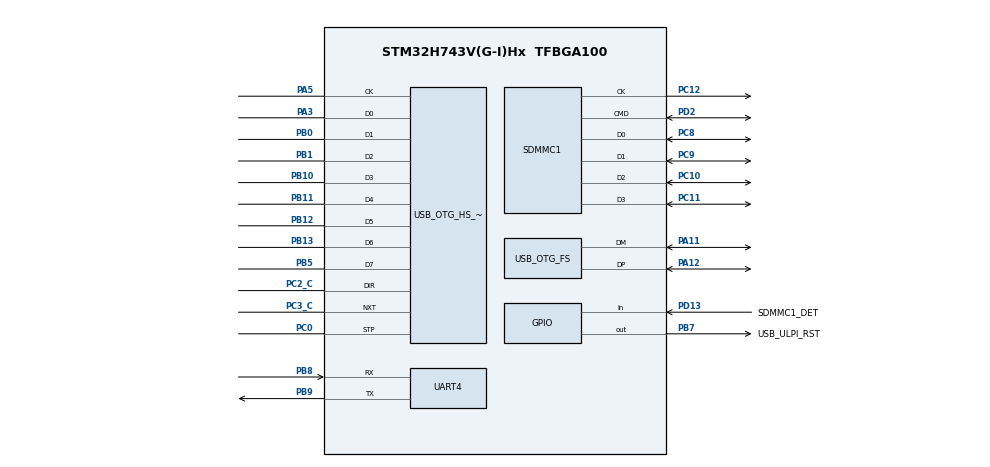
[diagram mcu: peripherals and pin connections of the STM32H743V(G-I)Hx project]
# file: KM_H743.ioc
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CORTEX_M7.default_mode_Activation=1
FATFS.BSP.number=1
FATFS._CODE_PAGE=949
FATFS._FS_EXFAT=1
FATFS._FS_RPATH=2
FATFS._USE_CHMOD=1
FATFS._USE_EXPAND=1
FATFS._USE_FIND=1
FATFS._USE_LFN=2
FATFS._USE_TRIM=0
FATFS0.BSP.STBoard=false
FATFS0.BSP.api=Unknown
FATFS0.BSP.instance=PD13
FATFS0.BSP.ip=GPIO
FATFS0.BSP.mode=Input
FATFS0.BSP.name=Detect_SDIO
FATFS0.BSP.solution=PD13
FREERTOS.Tasks01=defaultTask,24,1024,StartDefaultTask,Default,NULL,Static,defaultTaskStack,defaultTaskControl
FREERTOS.configMINIMAL_STACK_SIZE=512
FREERTOS.configTOTAL_HEAP_SIZE=8192
FREERTOS.configUSE_NEWLIB_REENTRANT=0
Mcu.Family=STM32H7
Mcu.Name=STM32H743V(G-I)Hx
Mcu.Package=TFBGA100
NVIC.OTG_FS_EP1_IN_IRQn=true\:5\:0\:false\:false\:true\:true\:true\:true\:true
NVIC.OTG_FS_EP1_OUT_IRQn=true\:5\:0\:false\:false\:true\:true\:true\:true\:true
NVIC.OTG_FS_IRQn=true\:5\:0\:false\:false\:true\:true\:true\:true\:true
NVIC.PriorityGroup=NVIC_PRIORITYGROUP_4
NVIC.TIM1_UP_IRQn=true\:15\:0\:false\:false\:true\:false\:false\:true\:true
NVIC.TimeBase=TIM1_UP_IRQn
NVIC.TimeBaseIP=TIM1
PA11.Mode=Device_Only
PA11.Signal=USB_OTG_FS_DM
PA12.Mode=Device_Only
PA12.Signal=USB_OTG_FS_DP
PA13\ (JTMS/SWDIO).Mode=Serial_Wire
PA13\ (JTMS/SWDIO).Signal=DEBUG_JTMS-SWDIO
PA14\ (JTCK/SWCLK).Mode=Serial_Wire
PA14\ (JTCK/SWCLK).Signal=DEBUG_JTCK-SWCLK
PA3.Mode=Device_HS
PA3.Signal=USB_OTG_HS_ULPI_D0
PA5.Mode=Device_HS
PA5.Signal=USB_OTG_HS_ULPI_CK
PB0.Mode=Device_HS
PB0.Signal=USB_OTG_HS_ULPI_D1
PB1.Mode=Device_HS
PB1.Signal=USB_OTG_HS_ULPI_D2
PB10.Mode=Device_HS
PB10.Signal=USB_OTG_HS_ULPI_D3
PB11.Mode=Device_HS
PB11.Signal=USB_OTG_HS_ULPI_D4
PB12.Mode=Device_HS
PB12.Signal=USB_OTG_HS_ULPI_D5
PB13.Mode=Device_HS
PB13.Signal=USB_OTG_HS_ULPI_D6
PB5.Mode=Device_HS
PB5.Signal=USB_OTG_HS_ULPI_D7
PB7.GPIO_Label=USB_ULPI_RST
PB7.Signal=GPIO_Output
PB8.Mode=Asynchronous
PB8.Signal=UART4_RX
PB9.Mode=Asynchronous
PB9.Signal=UART4_TX
PC0.Mode=Device_HS
PC0.Signal=USB_OTG_HS_ULPI_STP
PC10.Mode=SD_4_bits_Wide_bus
PC10.Signal=SDMMC1_D2
PC11.Mode=SD_4_bits_Wide_bus
PC11.Signal=SDMMC1_D3
PC12.Mode=SD_4_bits_Wide_bus
PC12.Signal=SDMMC1_CK
PC14-OSC32_IN\ (OSC32_IN).Mode=LSE-External-Oscillator
PC14-OSC32_IN\ (OSC32_IN).PinAttribute=Free
PC14-OSC32_IN\ (OSC32_IN).Signal=RCC_OSC32_IN
PC15-OSC32_OUT\ (OSC32_OUT).Mode=LSE-External-Oscillator
PC15-OSC32_OUT\ (OSC32_OUT).Signal=RCC_OSC32_OUT
PC2_C.Mode=Device_HS
PC2_C.Signal=USB_OTG_HS_ULPI_DIR
PC3_C.Mode=Device_HS
PC3_C.Signal=USB_OTG_HS_ULPI_NXT
PC8.Mode=SD_4_bits_Wide_bus
PC8.Signal=SDMMC1_D0
PC9.Mode=SD_4_bits_Wide_bus
PC9.Signal=SDMMC1_D1
PD13.GPIO_Label=SDMMC1_DET
PD13.Signal=GPIO_Input
PD2.Mode=SD_4_bits_Wide_bus
PD2.Signal=SDMMC1_CMD
PH0-OSC_IN\ (PH0).Mode=HSE-External-Oscillator
PH0-OSC_IN\ (PH0).Signal=RCC_OSC_IN
PH1-OSC_OUT\ (PH1).Mode=HSE-External-Oscillator
PH1-OSC_OUT\ (PH1).Signal=RCC_OSC_OUT
ProjectManager.HeapSize=0x200
ProjectManager.StackSize=0x400
ProjectManager.TargetToolchain=STM32CubeIDE
RCC.ADCFreq_Value=25000000
RCC.APB1Freq_Value=120000000
RCC.APB2Freq_Value=120000000
RCC.APB3Freq_Value=120000000
RCC.APB4Freq_Value=120000000
RCC.CortexFreq_Value=480000000
RCC.D1PPRE=RCC_APB3_DIV2
RCC.D2PPRE1=RCC_APB1_DIV2
RCC.D2PPRE2=RCC_APB2_DIV2
RCC.D3PPRE=RCC_APB4_DIV2
RCC.DIVM1=5
RCC.DIVM2=5
RCC.DIVM3=5
RCC.DIVN1=192
RCC.DIVN2=10
RCC.DIVN3=120
RCC.DIVP3=3
RCC.DIVQ1=20
RCC.DIVQ3=5
RCC.HCLKFreq_Value=240000000
RCC.HPRE=RCC_HCLK_DIV2
RCC.HSE_VALUE=25000000
RCC.PLL1_VCI_Range-AdvancedSettings=RCC_PLL1VCIRANGE_0
RCC.PLL2_VCI_Range-AdvancedSettings=RCC_PLL2VCIRANGE_0
RCC.PLL2_VCO_SEL-AdvancedSettings=RCC_PLL2VCOWIDE
RCC.PLL3_VCI_Range-AdvancedSettings=RCC_PLL3VCIRANGE_0
RCC.PLLSourceVirtual=RCC_PLLSOURCE_HSE
RCC.SPI123CLockSelection=RCC_SPI123CLKSOURCE_PLL3
RCC.SYSCLKFreq_VALUE=480000000
RCC.SYSCLKSource=RCC_SYSCLKSOURCE_PLLCLK
RCC.Spi45ClockSelection=RCC_SPI45CLKSOURCE_PLL3
RCC.USBFreq_Value=48000000
USB_OTG_FS.VirtualMode=Device_Only
SDMMC1.ClockDiv=1
USB_OTG_HS.VirtualMode-Device_HS=Device_HS
VP_FATFS_VS_SDIO.Mode=SDIO
VP_FREERTOS_VS_CMSIS_V2.Mode=CMSIS_V2
VP_MEMORYMAP_VS_MEMORYMAP.Mode=CurAppReg
VP_SYS_VS_tim1.Mode=TIM1
board=custom

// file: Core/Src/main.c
/* USER CODE BEGIN Header */
/**
  ******************************************************************************
  * @file           : main.c
  * @brief          : Main program body
  ******************************************************************************
  * @attention
  *
  * Copyright (c) 2026 STMicroelectronics.
  * All rights reserved.
  *
  * This software is licensed under terms that can be found in the LICENSE file
  * in the root directory of this software component.
  * If no LICENSE file comes with this software, it is provided AS-IS.
  *
  ******************************************************************************
  */
/* USER CODE END Header */
#include "main.h"
#include "cmsis_os.h"
#include "fatfs.h"

/* USER CODE BEGIN Includes */
#include "management_fs.h"
#include "target_usb.h"
#include "FreeRTOS.h"
#include "task.h"
#include <stdbool.h>

/* USER CODE END Includes */

SD_HandleTypeDef hsd1;

UART_HandleTypeDef huart4;

/* Definitions for defaultTask */
/* Static FreeRTOS storage for the initial system/diagnostics task. */
static StaticTask_t defaultTaskControl;
static StackType_t defaultTaskStack[4096 / sizeof(StackType_t)]
    __attribute__((section(".rtos_stacks"), aligned(8)));
osThreadId_t defaultTaskHandle;
const osThreadAttr_t defaultTask_attributes = {
  .name = "defaultTask",
  .cb_mem = &defaultTaskControl,
  .cb_size = sizeof(defaultTaskControl),
  .stack_mem = defaultTaskStack,
  .stack_size = sizeof(defaultTaskStack),
  .priority = (osPriority_t) osPriorityNormal,
};

void SystemClock_Config(void);
static void MX_GPIO_Init(void);
static void MX_SDMMC1_SD_Init(void);
static void MX_UART4_Init(void);
void StartDefaultTask(void *argument);

int main(void)
{

  /* MCU Configuration--------------------------------------------------------*/

  /* Reset of all peripherals, Initializes the Flash interface and the Systick. */
  if (HAL_Init() != HAL_OK)
  {
    Error_Handler();
  }

  /* Configure the system clock */
  SystemClock_Config();

  /* Initialize all configured peripherals */
  MX_GPIO_Init();
  MX_SDMMC1_SD_Init();
  MX_UART4_Init();
  MX_FATFS_Init();

  /* Init scheduler */
  if (osKernelInitialize() != osOK)
  {
    Error_Handler();
  }

  /* Create the thread(s) */
  /* creation of defaultTask */
  defaultTaskHandle = osThreadNew(StartDefaultTask, NULL, &defaultTask_attributes);

  /* USER CODE BEGIN RTOS_THREADS */
  if (defaultTaskHandle == NULL || retSD != 0U)
  {
    Error_Handler();
  }
  UsbBoard_InitClock();
#ifndef MINIKMB_USB_HS_ONLY
  ManagementUsb_Start();
#endif
  TargetUsb_Start();
  /* USER CODE END RTOS_THREADS */

  /* Start scheduler */
  (void)osKernelStart();
  Error_Handler();

  /* We should never get here as control is now taken by the scheduler */

  /* Infinite loop */
  while (1)
  {

  }
}

void SystemClock_Config(void)
{
  RCC_OscInitTypeDef RCC_OscInitStruct = {0};
  RCC_ClkInitTypeDef RCC_ClkInitStruct = {0};

  /** Supply configuration update enable
  */
  if (HAL_PWREx_ConfigSupply(PWR_LDO_SUPPLY) != HAL_OK)
  {
    Error_Handler();
  }

  /** Configure the main internal regulator output voltage
  */
  /* Keep USB/RNG at 48 MHz while reducing Cortex-M7 and AHB power. */
  bool fast_clock = false;
#if defined(MINIKMB_CPU_480MHZ) && MINIKMB_CPU_480MHZ
  fast_clock = HAL_GetREVID() == REV_ID_V;
#endif
  const uint32_t vos = fast_clock ? PWR_REGULATOR_VOLTAGE_SCALE0 : PWR_REGULATOR_VOLTAGE_SCALE1;
  if (HAL_PWREx_ControlVoltageScaling(vos) != HAL_OK)
  {
    Error_Handler();
  }

  /** Initializes the RCC Oscillators according to the specified parameters
  * in the RCC_OscInitTypeDef structure.
  */
  RCC_OscInitStruct.OscillatorType = RCC_OSCILLATORTYPE_HSE;
  RCC_OscInitStruct.HSEState = RCC_HSE_ON;
  RCC_OscInitStruct.PLL.PLLState = RCC_PLL_ON;
  RCC_OscInitStruct.PLL.PLLSource = RCC_PLLSOURCE_HSE;
  RCC_OscInitStruct.PLL.PLLM = 5;
  if (!fast_clock)
  {
    /* 25 / 5 * 96 = 480 MHz VCO; 240 MHz CPU, 120 MHz AHB, Q=10. */
    RCC_OscInitStruct.PLL.PLLN = 96;
    RCC_OscInitStruct.PLL.PLLQ = 10;
  }
  else
  {
    RCC_OscInitStruct.PLL.PLLN = 192;
    RCC_OscInitStruct.PLL.PLLQ = 20;
  }
  RCC_OscInitStruct.PLL.PLLP = 2;
  RCC_OscInitStruct.PLL.PLLR = 2;
  RCC_OscInitStruct.PLL.PLLRGE = RCC_PLL1VCIRANGE_2;
  RCC_OscInitStruct.PLL.PLLVCOSEL = RCC_PLL1VCOWIDE;
  RCC_OscInitStruct.PLL.PLLFRACN = 0;
  if (HAL_RCC_OscConfig(&RCC_OscInitStruct) != HAL_OK)
  {
    Error_Handler();
  }

  /** Initializes the CPU, AHB and APB buses clocks
  */
  RCC_ClkInitStruct.ClockType = RCC_CLOCKTYPE_HCLK|RCC_CLOCKTYPE_SYSCLK
                              |RCC_CLOCKTYPE_PCLK1|RCC_CLOCKTYPE_PCLK2
                              |RCC_CLOCKTYPE_D3PCLK1|RCC_CLOCKTYPE_D1PCLK1;
  RCC_ClkInitStruct.SYSCLKSource = RCC_SYSCLKSOURCE_PLLCLK;
  RCC_ClkInitStruct.SYSCLKDivider = RCC_SYSCLK_DIV1;
  RCC_ClkInitStruct.AHBCLKDivider = RCC_HCLK_DIV2;
  RCC_ClkInitStruct.APB3CLKDivider = RCC_APB3_DIV2;
  RCC_ClkInitStruct.APB1CLKDivider = RCC_APB1_DIV2;
  RCC_ClkInitStruct.APB2CLKDivider = RCC_APB2_DIV2;
  RCC_ClkInitStruct.APB4CLKDivider = RCC_APB4_DIV2;

  if (HAL_RCC_ClockConfig(&RCC_ClkInitStruct, FLASH_LATENCY_4) != HAL_OK)
  {
    Error_Handler();
  }
}

static void MX_SDMMC1_SD_Init(void)
{

  hsd1.Instance = SDMMC1;
  hsd1.Init.ClockEdge = SDMMC_CLOCK_EDGE_RISING;
  hsd1.Init.ClockPowerSave = SDMMC_CLOCK_POWER_SAVE_DISABLE;
  hsd1.Init.BusWide = SDMMC_BUS_WIDE_4B;
  hsd1.Init.HardwareFlowControl = SDMMC_HARDWARE_FLOW_CONTROL_DISABLE;
  /* Card I/O starts from FatFs disk_initialize in task context. */
  hsd1.Init.ClockDiv = 1;

}

static void MX_UART4_Init(void)
{

  huart4.Instance = UART4;
  huart4.Init.BaudRate = 115200;
  huart4.Init.WordLength = UART_WORDLENGTH_8B;
  huart4.Init.StopBits = UART_STOPBITS_1;
  huart4.Init.Parity = UART_PARITY_NONE;
  huart4.Init.Mode = UART_MODE_TX_RX;
  huart4.Init.HwFlowCtl = UART_HWCONTROL_NONE;
  huart4.Init.OverSampling = UART_OVERSAMPLING_16;
  huart4.Init.OneBitSampling = UART_ONE_BIT_SAMPLE_DISABLE;
  huart4.Init.ClockPrescaler = UART_PRESCALER_DIV1;
  huart4.AdvancedInit.AdvFeatureInit = UART_ADVFEATURE_NO_INIT;
  if (HAL_UART_Init(&huart4) != HAL_OK)
  {
    Error_Handler();
  }
  if (HAL_UARTEx_SetTxFifoThreshold(&huart4, UART_TXFIFO_THRESHOLD_1_8) != HAL_OK)
  {
    Error_Handler();
  }
  if (HAL_UARTEx_SetRxFifoThreshold(&huart4, UART_RXFIFO_THRESHOLD_1_8) != HAL_OK)
  {
    Error_Handler();
  }
  if (HAL_UARTEx_DisableFifoMode(&huart4) != HAL_OK)
  {
    Error_Handler();
  }

}

static void MX_GPIO_Init(void)
{
  GPIO_InitTypeDef GPIO_InitStruct = {0};

  /* GPIO Ports Clock Enable */
  __HAL_RCC_GPIOC_CLK_ENABLE();
  __HAL_RCC_GPIOB_CLK_ENABLE();
  __HAL_RCC_GPIOA_CLK_ENABLE();
  __HAL_RCC_GPIOD_CLK_ENABLE();
  __HAL_RCC_GPIOH_CLK_ENABLE();

  /*Configure GPIO pin Output Level */
  HAL_GPIO_WritePin(USB_ULPI_RST_GPIO_Port, USB_ULPI_RST_Pin, GPIO_PIN_RESET);

  /*Configure GPIO pin : USB_ULPI_RST_Pin */
  GPIO_InitStruct.Pin = USB_ULPI_RST_Pin;
  GPIO_InitStruct.Mode = GPIO_MODE_OUTPUT_PP;
  GPIO_InitStruct.Pull = GPIO_NOPULL;
  GPIO_InitStruct.Speed = GPIO_SPEED_FREQ_LOW;
  HAL_GPIO_Init(USB_ULPI_RST_GPIO_Port, &GPIO_InitStruct);

  /*Configure GPIO pin : SDMMC1_DET_Pin */
  GPIO_InitStruct.Pin = SDMMC1_DET_Pin;
  GPIO_InitStruct.Mode = GPIO_MODE_INPUT;
  GPIO_InitStruct.Pull = GPIO_NOPULL;
  HAL_GPIO_Init(SDMMC1_DET_GPIO_Port, &GPIO_InitStruct);

}

void StartDefaultTask(void *argument)
{
  /* USER CODE BEGIN 5 */
  /* Infinite loop */
  for(;;)
  {
    osDelay(1000);
  }
  /* USER CODE END 5 */
}

void HAL_TIM_PeriodElapsedCallback(TIM_HandleTypeDef *htim)
{
  if (htim->Instance == TIM1)
  {
    HAL_IncTick();
  }
}

void Error_Handler(void)
{
  __disable_irq();
  while (1)
  {
  }
}

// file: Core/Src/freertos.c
/* USER CODE BEGIN Header */
/**
  ******************************************************************************
  * File Name          : freertos.c
  * Description        : Code for freertos applications
  ******************************************************************************
  * @attention
  *
  * Copyright (c) 2026 STMicroelectronics.
  * All rights reserved.
  *
  * This software is licensed under terms that can be found in the LICENSE file
  * in the root directory of this software component.
  * If no LICENSE file comes with this software, it is provided AS-IS.
  *
  ******************************************************************************
  */
/* USER CODE END Header */

#include "FreeRTOS.h"
#include "task.h"
#include "main.h"

/* USER CODE BEGIN Includes */
#include <stdint.h>

/* USER CODE END Includes */

/* USER CODE BEGIN Variables */
uint8_t ucHeap[configTOTAL_HEAP_SIZE] __attribute__((section(".rtos_heap"), aligned(32)));

static StaticTask_t idleControl;
static StaticTask_t timerControl;
static StackType_t idleStack[configMINIMAL_STACK_SIZE]
    __attribute__((section(".rtos_stacks"), aligned(8)));
static StackType_t timerStack[configTIMER_TASK_STACK_DEPTH]
    __attribute__((section(".rtos_stacks"), aligned(8)));

/* Available to SWD before the USB diagnostic transport is implemented. */
static volatile uint32_t allocationFailures;

/* USER CODE END Variables */

/* USER CODE BEGIN Application */
extern uint32_t g_pfnVectors[];
extern uint64_t __axi_start__[], __axi_end__[];
extern uint32_t __d2_start__[], __d2_end__[];

void BoardMemory_Init(void)
{
  static const struct
  {
    uint32_t base;
    uint8_t size;
    uint8_t permission;
    uint8_t execute;
    uint8_t tex;
    uint8_t cacheable;
    uint8_t bufferable;
    uint8_t shareable;
  } regions[] = {
    /* base, size, AP, XN, TEX, C, B, S */
    {0x08000000U, MPU_REGION_SIZE_2MB,  MPU_REGION_PRIV_RO_URO, 0, 0, 1, 0, 0},
    {0x20000000U, MPU_REGION_SIZE_128KB, MPU_REGION_FULL_ACCESS, 1, 1, 0, 0, 0},
    {0x20018000U, MPU_REGION_SIZE_16KB, MPU_REGION_NO_ACCESS,   1, 1, 0, 0, 0},
    {0x24000000U, MPU_REGION_SIZE_512KB, MPU_REGION_FULL_ACCESS, 1, 1, 1, 1, 0},
    {0x24060000U, MPU_REGION_SIZE_128KB, MPU_REGION_FULL_ACCESS, 1, 1, 0, 0, 1},
    {0x30000000U, MPU_REGION_SIZE_256KB, MPU_REGION_FULL_ACCESS, 1, 1, 1, 1, 0},
    {0x30040000U, MPU_REGION_SIZE_32KB, MPU_REGION_FULL_ACCESS, 1, 1, 1, 1, 0},
    {0x38000000U, MPU_REGION_SIZE_64KB, MPU_REGION_FULL_ACCESS, 1, 1, 0, 0, 0},
    {0x00000000U, MPU_REGION_SIZE_64KB, MPU_REGION_NO_ACCESS,   1, 1, 0, 0, 0},
  };

  /* Setting VTOR explicitly also prevents the ITCM guard catching vector fetches. */
  SCB->VTOR = (uint32_t)g_pfnVectors;
  __DSB();
  __ISB();
  /* Reset leaves the cache disabled and potentially uninitialized.
     Cleaning invalid tag RAM before the first invalidate can fault. */
  if ((SCB->CCR & SCB_CCR_DC_Msk) != 0U)
  {
    SCB_DisableDCache();
  }
  if ((SCB->CCR & SCB_CCR_IC_Msk) != 0U)
  {
    SCB_DisableICache();
  }
  HAL_MPU_Disable();

  __HAL_RCC_D2SRAM1_CLK_ENABLE();
  __HAL_RCC_D2SRAM2_CLK_ENABLE();
  __HAL_RCC_D2SRAM3_CLK_ENABLE();
  /* H743 SRAM4 has no run-mode RCC enable; crash record is reserved only. */
  for (uintptr_t address = (uintptr_t)__d2_start__; address < (uintptr_t)__d2_end__; address += 4U)
  {
    *(volatile uint32_t *)address = 0U;
  }
  /* A VSTR.D makes each AXI ECC initialization write a full aligned word. */
  const uint64_t zero = 0U;
  for (uintptr_t address = (uintptr_t)__axi_start__; address < (uintptr_t)__axi_end__; address += 8U)
  {
    __asm volatile ("vstr %P0, [%1]" :: "w" (zero), "r" (address) : "memory");
  }
  __DSB();

  for (uint32_t number = 0; number < (sizeof(regions) / sizeof(regions[0])); ++number)
  {
    MPU_Region_InitTypeDef region = {
      .Enable = MPU_REGION_ENABLE,
      .Number = (uint8_t)number,
      .BaseAddress = regions[number].base,
      .Size = regions[number].size,
      .TypeExtField = regions[number].tex,
      .AccessPermission = regions[number].permission,
      .DisableExec = regions[number].execute,
      .IsShareable = regions[number].shareable,
      .IsCacheable = regions[number].cacheable,
      .IsBufferable = regions[number].bufferable,
    };
    HAL_MPU_ConfigRegion(&region);
  }

  HAL_MPU_Enable(MPU_PRIVILEGED_DEFAULT);
  SCB_EnableICache();
  SCB_EnableDCache();
}

void vApplicationGetIdleTaskMemory(StaticTask_t **control, StackType_t **stack,
                                   uint32_t *depth)
{
  *control = &idleControl;
  *stack = idleStack;
  *depth = configMINIMAL_STACK_SIZE;
}

void vApplicationGetTimerTaskMemory(StaticTask_t **control, StackType_t **stack,
                                    uint32_t *depth)
{
  *control = &timerControl;
  *stack = timerStack;
  *depth = configTIMER_TASK_STACK_DEPTH;
}

void vApplicationStackOverflowHook(TaskHandle_t task, char *name)
{
  (void)task;
  (void)name;
  Error_Handler();
}

void vApplicationMallocFailedHook(void)
{
  /* Reserve accounting for kernel task allocation. Application buffers are static. */
  taskENTER_CRITICAL();
  ++allocationFailures;
  taskEXIT_CRITICAL();
}

/* USER CODE END Application */
